VERSION 5.7 ;
  NOWIREEXTENSIONATPIN ON ;
  DIVIDERCHAR "/" ;
  BUSBITCHARS "[]" ;
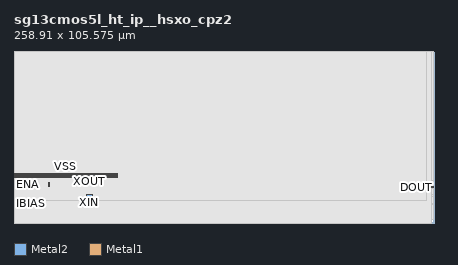
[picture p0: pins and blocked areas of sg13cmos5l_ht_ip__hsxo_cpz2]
MACRO sg13cmos5l_ht_ip__hsxo_cpz2
  CLASS BLOCK ;
  FOREIGN sg13cmos5l_ht_ip__hsxo_cpz2 ;
  ORIGIN 0.000 8.315 ;
  SIZE 258.910 BY 105.575 ;
  PIN XOUT
    ANTENNADIFFAREA 163.279999 ;
    PORT
      LAYER Metal2 ;
        RECT 44.470 16.620 48.140 17.620 ;
    END
  END XOUT
  PIN XIN
    ANTENNAGATEAREA 14.580000 ;
    PORT
      LAYER Metal2 ;
        RECT 44.420 8.325 48.175 9.325 ;
    END
  END XIN
  PIN ENA
    ANTENNAGATEAREA 0.226200 ;
    PORT
      LAYER Metal2 ;
        RECT 1.365 14.655 1.665 16.715 ;
    END
  END ENA
  PIN STDBY
    ANTENNAGATEAREA 11.052600 ;
    PORT
      LAYER Metal2 ;
        RECT 21.365 14.475 21.665 16.715 ;
    END
  END STDBY
  PIN DOUT
    ANTENNAGATEAREA 0.600000 ;
    ANTENNADIFFAREA 5.954400 ;
    PORT
      LAYER Metal2 ;
        RECT 253.410 13.265 258.695 14.265 ;
    END
  END DOUT
  PIN AVDD
    ANTENNADIFFAREA 63.647999 ;
    PORT
      LAYER Metal1 ;
        RECT 0.030 19.440 64.030 19.940 ;
    END
  END AVDD
  PIN DVDD
    ANTENNADIFFAREA 23.500599 ;
    PORT
      LAYER Metal1 ;
        RECT 0.030 20.440 64.030 20.940 ;
    END
  END DVDD
  PIN VSS
    USE GROUND ;
    PORT
      LAYER Metal1 ;
        RECT 0.030 21.440 64.030 21.940 ;
    END
  END VSS
  PIN IBIAS
    ANTENNADIFFAREA 9.728000 ;
    PORT
      LAYER Metal2 ;
        RECT 1.465 3.195 7.915 3.785 ;
    END
  END IBIAS
  OBS
      LAYER GatPoly ;
        RECT 0.340 0.310 258.600 21.470 ;
      LAYER Metal1 ;
        RECT 0.000 22.120 258.530 97.260 ;
        RECT 64.210 21.260 258.530 22.120 ;
        RECT 0.000 21.120 258.530 21.260 ;
        RECT 64.210 20.260 258.530 21.120 ;
        RECT 0.000 20.120 258.530 20.260 ;
        RECT 64.210 19.260 258.530 20.120 ;
        RECT 0.000 -3.000 258.530 19.260 ;
      LAYER Metal2 ;
        RECT 0.030 17.830 258.330 97.260 ;
        RECT 0.030 16.925 44.260 17.830 ;
        RECT 0.030 14.445 1.155 16.925 ;
        RECT 1.875 14.445 21.155 16.925 ;
        RECT 0.030 14.265 21.155 14.445 ;
        RECT 21.875 16.410 44.260 16.925 ;
        RECT 48.350 16.410 258.330 17.830 ;
        RECT 21.875 14.475 258.330 16.410 ;
        RECT 21.875 14.265 253.200 14.475 ;
        RECT 0.030 13.055 253.200 14.265 ;
        RECT 0.030 9.535 258.330 13.055 ;
        RECT 0.030 8.115 44.210 9.535 ;
        RECT 48.385 8.115 258.330 9.535 ;
        RECT 0.030 3.995 258.330 8.115 ;
        RECT 0.030 2.985 1.255 3.995 ;
        RECT 8.125 2.985 258.330 3.995 ;
        RECT 0.030 -6.405 258.330 2.985 ;
      LAYER Metal3 ;
        RECT 0.030 -8.315 257.535 97.260 ;
      LAYER Metal4 ;
        RECT 0.030 5.305 254.030 97.260 ;
  END
END sg13cmos5l_ht_ip__hsxo_cpz2
END LIBRARY

